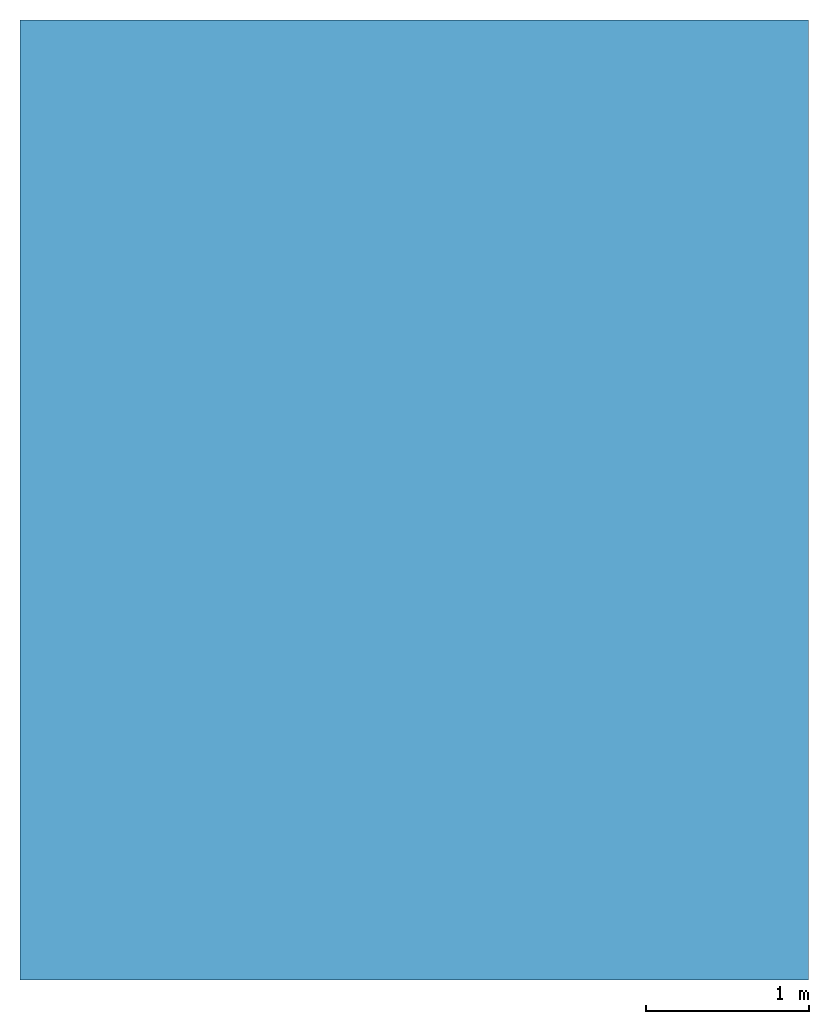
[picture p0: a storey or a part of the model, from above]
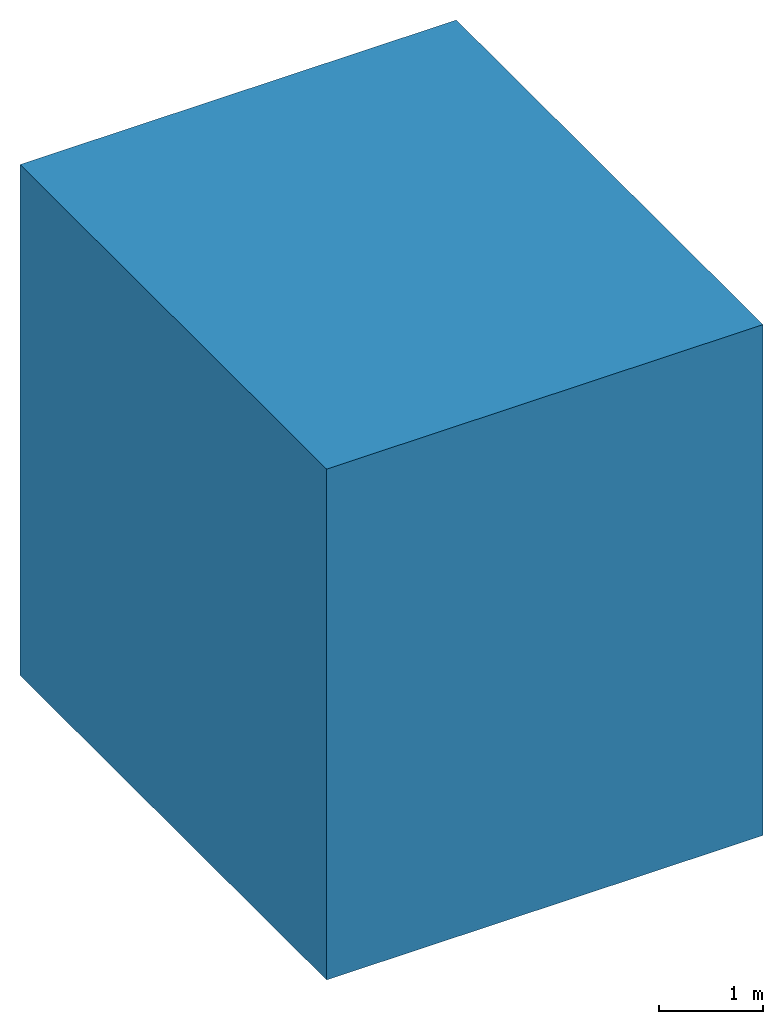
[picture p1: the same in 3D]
Properties of the parts of a building model (IFC2X3)

# File
Description: ViewDefinition [CoordinationView_V2.0]
File name: Project Number
Time: 2020-12-09T18:23:51
Written by: The EXPRESS Data Manager Version 5.02.0100.07 : 28 Aug 2013
Made in: 20190108_1515(x64) - Exporter 19.4.1.0 - Alternate UI 19.4.1.0
Comment: STEP Physical File produced by: The EXPRESS Data Manager Version 5.02.0100.07 : 28 Aug 2013 * Module: EDMstepFileFactory/EDMstandAlone * Creation date: Wed Dec 09 18:23:51 2020 * Host: OMEN-10 * Database: C:\Users\Eipm02\AppData\Local\Temp\{1E9CF5F9-0A56-40BF-BE97-BA38C275F90F}\ifc * Database version: 5507 * Database creation date: Wed Dec 09 18:23:51 2020 * Schema: IFC2X3 * Model: DataRepository.ifc * Model creation date: Wed Dec 09 18:23:51 2020 * Header model: DataRepository.ifc_HeaderModel * Header model creation date: Wed Dec 09 18:23:51 2020 * EDMuser: sdai-user * EDMgroup: sdai-group * License ID and type: 5605 : Permanent license. Expiry date: * EDMstepFileFactory options: 020000

# IfcProject, Project Number
LongName: Project Name; Phase: Project Status

# IfcSite, Default
RefLatitude: 42, 21, 31, 181945; RefLongitude: -71, -3, -24, -263305; RefElevation: 57 m
Pset_ProductRequirements - Category: Project Information

# IfcBuilding
Pset_BuildingCommon - NumberOfStoreys: 2
Pset_ProductRequirements - Category: Project Information

# IfcBuildingStorey: Level:8mm Head (2)
Pset_ProductRequirements - Category: Levels
Name | LongName | Elevation (m) | Pset_AirSideSystemInformation, Name = Pset_ProductRequirements, Name
Level 1 | Level 1 | 1 | Altura interno
Level 2 | Level 2 | 7 | Level 2

# IfcBuildingElementProxy: Generic Models 1:Generic Models 1, Generic Models 1:Generic Models 1:202366
In: Level 1
Type - Material: <Unnamed>
Type - Pset_BuildingElementProxyCommon - Reference: Generic Models 1
Type - Pset_ProductRequirements - Category: Generic Models
Type - Pset_QuantityTakeOff - Reference: Generic Models 1
Pset_BuildingElementProxyCommon - sets with these values: 2
Pset_ProvisionForVoid - Width: 6 m; Height: 2.58609 m; Depth: 6 m

# IfcSlab: Floor:XCA_Floor_6m, Floor:XCA_Floor_6m:202272
In: Level 2
Type - PredefinedType: FLOOR; Material: Default Roof 6 m
Type - Pset_ElementShading - Roughness: 0.3048 m
Type - Pset_ProductRequirements - Category: Floors
Type - Pset_QuantityTakeOff - Reference: XCA_Floor_6m
Type - Pset_ReinforcementBarPitchOfSlab - Reference: XCA_Floor_6m
Type - Pset_SlabCommon - IsExternal: no; Reference: XCA_Floor_6m
Pset_QuantityTakeOff - sets with these values: 2
Pset_SlabCommon - LoadBearing: no; PitchAngle: 0 deg

# IfcWallStandardCase: Basic Wall:Generic - 200mm, Basic Wall:Generic - 200mm:202033
In: Level 1
Type - PredefinedType: STANDARD; Material: Default Wall 0.2 m
Type - Pset_ElementShading - Roughness: 0.3048 m
Type - Pset_ProductRequirements - Category: Walls
Type - Pset_QuantityTakeOff - Reference: Generic - 200mm
Type - Pset_ReinforcementBarPitchOfWall - Reference: Generic - 200mm
Type - Pset_WallCommon - Reference: Generic - 200mm; IsExternal: no
Pset_QuantityTakeOff - sets with these values: 2
Pset_WallCommon - IsExternal: yes; ExtendToStructure: no; LoadBearing: no
